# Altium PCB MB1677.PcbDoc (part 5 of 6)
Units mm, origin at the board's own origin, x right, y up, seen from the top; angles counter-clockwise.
Board outline 78 x 105 mm, 6 copper layers (Top Layer, Signal Layer 1, Signal Layer 2, Signal Layer 3, Signal Layer 4, Bottom Layer), stack 1.574 mm thick; 395 components, 320 nets, 1673 pads, 974 vias.

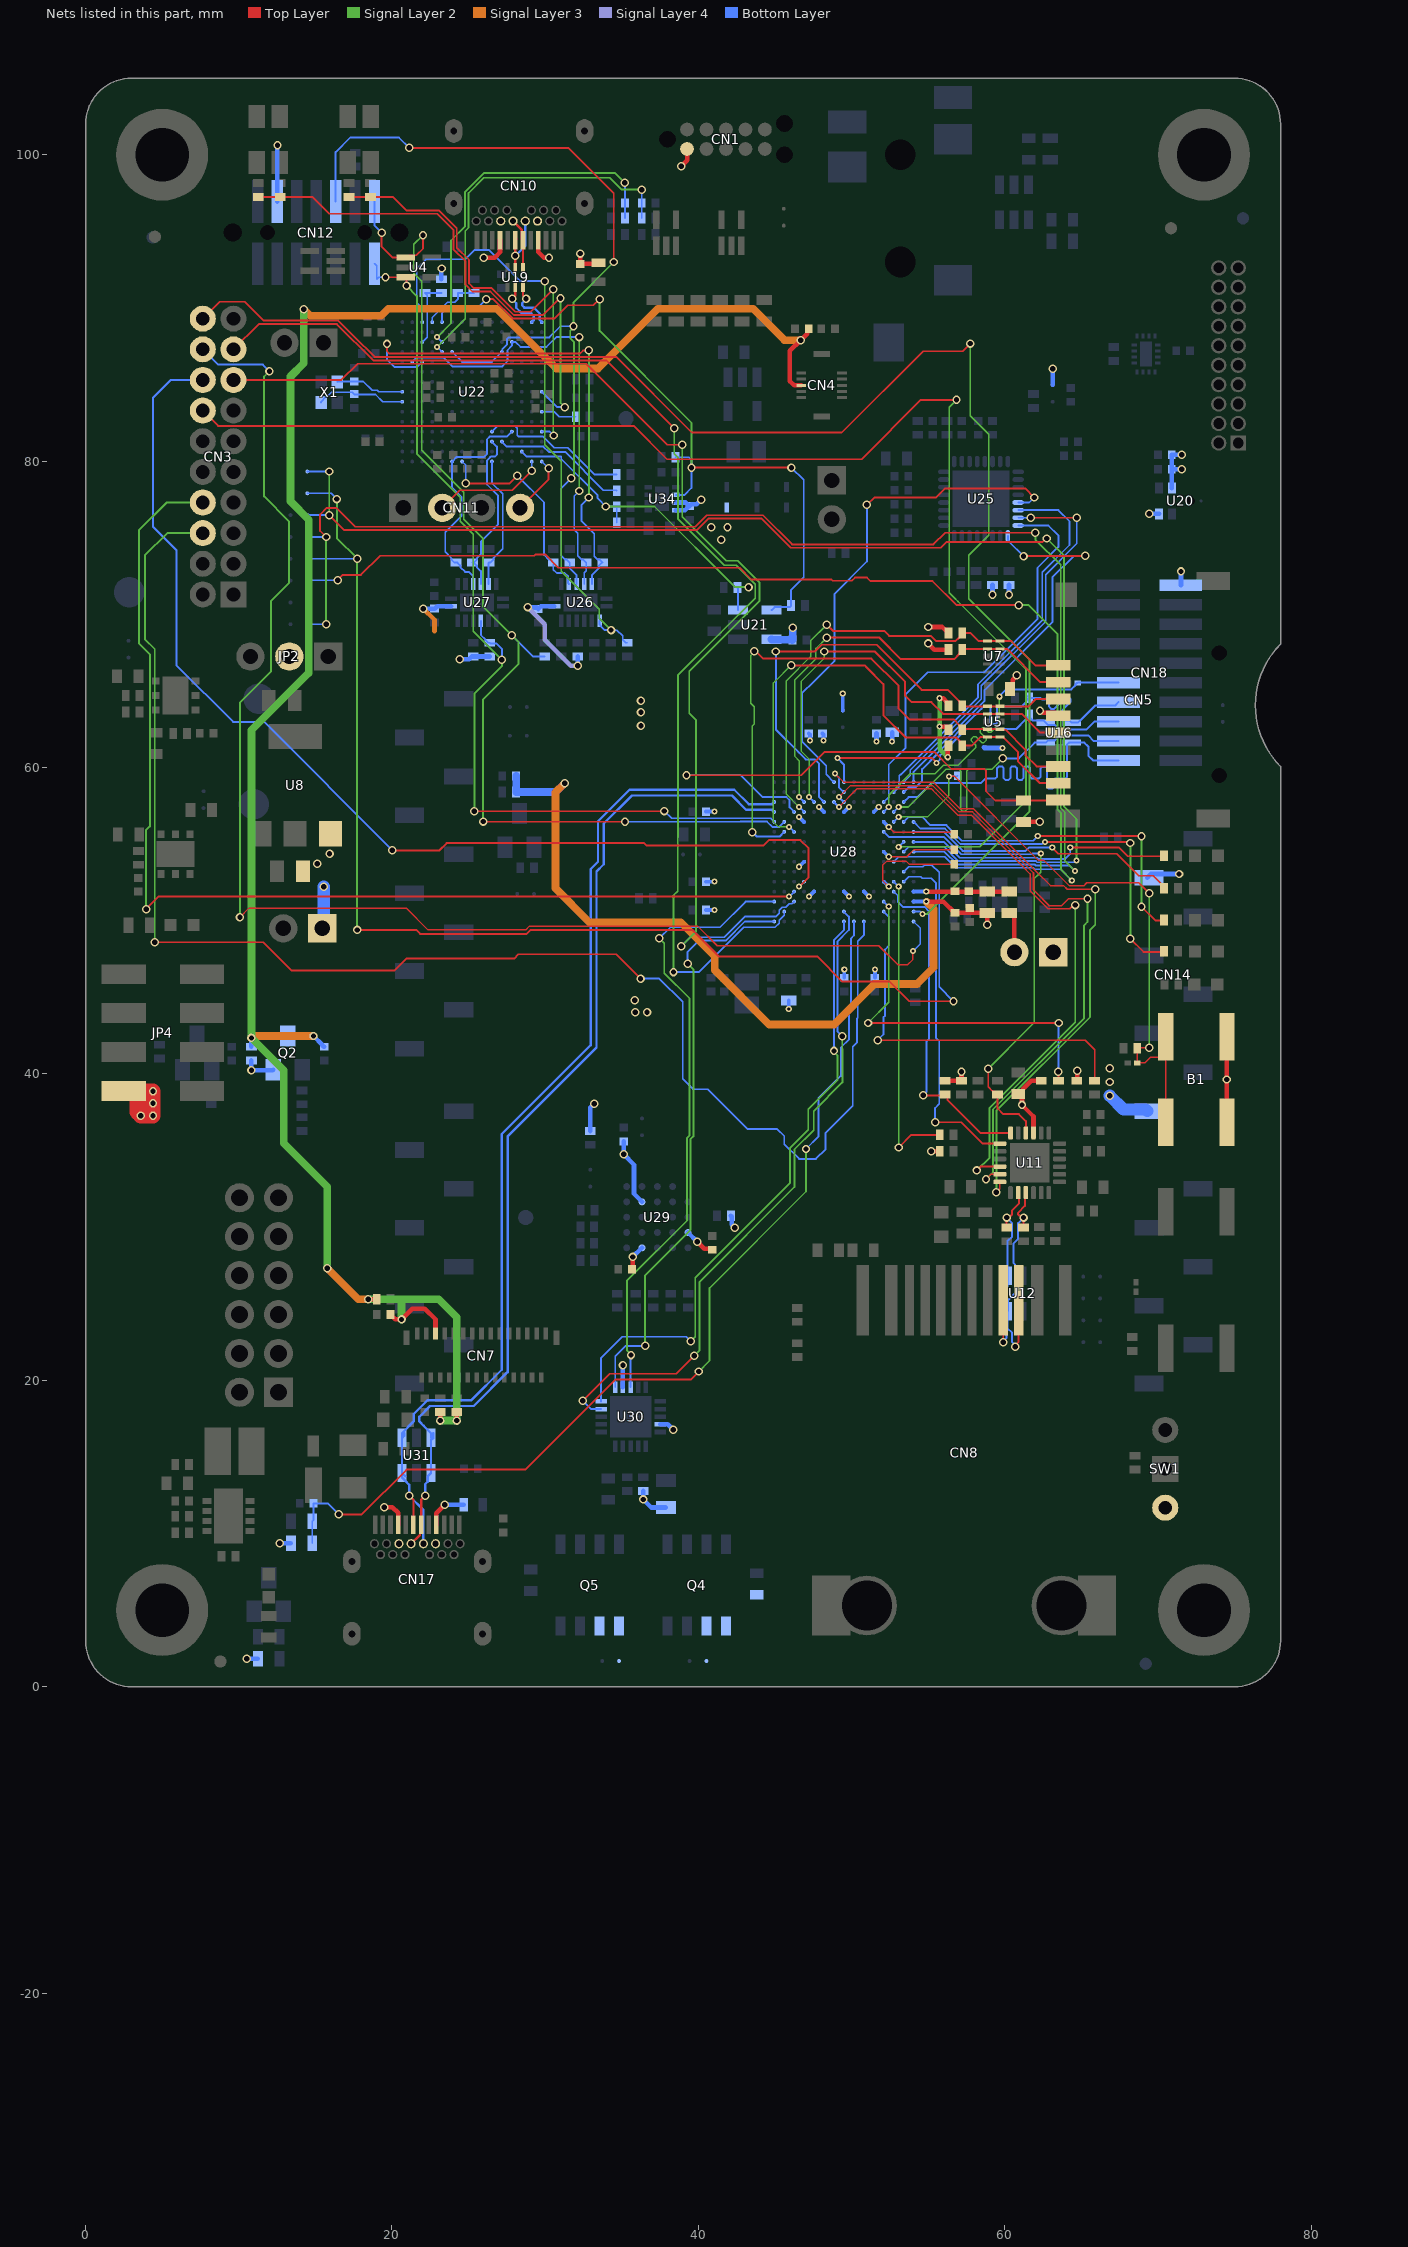
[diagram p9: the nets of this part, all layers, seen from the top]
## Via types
v1: diameter 0.55, hole 0.35, Top Layer to Bottom Layer, tented both sides, 762 vias
v2: diameter 0.4, hole 0.2, Top Layer to Bottom Layer, tented both sides, 203 vias
v3: diameter 0.6, hole 0.3, Top Layer to Bottom Layer, tented both sides, 9 vias

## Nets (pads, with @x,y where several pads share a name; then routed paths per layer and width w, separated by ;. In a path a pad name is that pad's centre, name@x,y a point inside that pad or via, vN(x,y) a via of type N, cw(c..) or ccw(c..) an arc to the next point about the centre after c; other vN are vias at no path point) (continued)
RMII_MDC: U11.13 U28.L2 | length 23
  Top Layer w0.12: v1(55.45,36.85) 57.15,36.85 58.55,35.45 U11.13@59.675,35.45
  Bottom Layer w0.12: U28.L2@53.4,52.55 53.725,52.875 54.5,52.875 54.6,52.775 55.193,52.775 55.5,52.468 55.5,44.275 55.5,42.375 55.725,42.15 55.725,41.625 55.725,38.05 55.45,37.775 v1(55.45,36.85)
RMII_MDIO: R34.1 U11.12 U28.M3 | length 22.1
  Top Layer w0.12: v1(54.675,38.6) 56.05,38.6 R34.1@56.1,38.65 56.265,38.485 56.265,38.285 58.4,36.15 U11.12@60.375,36.15
  Bottom Layer w0.12: U28.M3@52.75,51.9 53.035,51.615 53.035,51.212 53.347,50.9 54.775,50.9 55.05,50.625 55.05,42.275 54.9,42.125 54.9,38.825 v1(54.675,38.6)
RMII_REF_CLK: R37.1 U28.L3 | length 20.5
  Top Layer w0.12: v1(53.075,35.2) 53.9,36.025 R37.1@55.75,36.025
  Signal Layer 2 w0.1: 53.075,41.625 v2(53.075,52.225)
  Signal Layer 2 w0.12: v1(53.075,35.2) 53.075,41.625
  Bottom Layer w0.13: U28.L3@52.75,52.55 v2(53.075,52.225)
RMII_RX_ER: R29.1 U11.10 U28.F4 | length 32.2
  Top Layer w0.12: v1(58.925,40.35) 58.925,39.15 59.23,38.845 59.33,38.845 R29.1@59.525,38.65 59.525,37.75 59.9,37.375 60.925,37.375 61.375,36.925 U11.10@61.375,36.15
  Signal Layer 2 w0.1: 60.2,41.625 61.925,43.35 61.925,52.75 62.125,52.95
  Signal Layer 2 w0.12: v1(58.925,40.35) 60.2,41.625 ; 62.125,52.95 62.35,53.175 v2(62.35,54.4)
  Bottom Layer w0.12: U28.F4@52.1,55.8 52.425,55.475 56.016,55.475 57.156,54.335 61.752,54.335 61.817,54.4 v2(62.35,54.4)
RMII_RXD0: R31.1 U28.N4 | length 24.9
  Top Layer w0.1: v1(51.075,43.325) 62.125,43.325
  Top Layer w0.12: 62.125,43.325 v1(63.525,43.325) ; R31.1@63.5,39.55 63.5,40.125 v1(63.5,40.15)
  Signal Layer 2 w0.1: v1(51.075,43.325) 52.425,44.675 v2(52.425,50.925)
  Bottom Layer w0.12: v1(63.5,40.15) 63.5,43.3 v1(63.525,43.325)
  Bottom Layer w0.13: U28.N4@52.1,51.25 v2(52.425,50.925)
RMII_RXD1: R33.1 U28.P4 | length 25.3
  Top Layer w0.12: v1(51.7,42.2) 62.125,42.2 65.25,42.2 65.55,41.9 65.875,41.575 65.875,39.575 R33.1@65.85,39.55
  Bottom Layer w0.12: v1(51.7,42.2) 52.075,42.575 52.075,43.69 52.185,43.8 52.185,48.124 52.425,48.364 52.425,50.275 U28.P4@52.1,50.6
RMII_TX_EN: U11.16 U28.C9 | length 42
  Top Layer w0.1: v2(49.175,57.425) 50.375,58.625 55.2,58.625 55.512,58.312 56.925,56.9 57.809,56.9 61.3,53.409 61.392,53.317 61.65,53.059 61.65,51.958 62.125,51.483 62.823,50.785 64.238,50.785 64.478,51.025 v1(64.6,51.025)
  Top Layer w0.12: v1(58.175,33.7) 58.425,33.95 U11.16@59.675,33.95
  Signal Layer 2 w0.12: v1(58.175,33.7) 59.01,34.535 59.01,37.782 64.6,43.372 v1(64.6,51.025)
  Bottom Layer w0.13: U28.C9@48.85,57.75 v2(49.175,57.425)
RMII_TXD0: U11.17 U28.C8 | length 43.2
  Top Layer w0.1: v2(49.175,58.075) 49.925,58.825 55.283,58.825 57.008,57.1 57.892,57.1 61.875,53.117 61.875,52.016 62.029,51.862 62.906,50.985 63.71,50.985 64.175,51.45 65.375,51.45 v1(65.4,51.425)
  Top Layer w0.12: v1(58.775,33.125) 59.1,33.45 U11.17@59.675,33.45
  Signal Layer 2 w0.12: v1(58.775,33.125) 59.23,33.58 59.23,37.691 65.175,43.636 65.175,49.7 65.4,49.925 v1(65.4,51.425)
  Bottom Layer w0.13: v2(49.175,58.075) U28.C8@49.5,57.75
RMII_TXD1: U11.18 U28.B8 | length 44.8
  Top Layer w0.1: v2(48.925,59.6) 49.5,59.025 55.366,59.025 56.095,58.295 57.091,57.3 57.975,57.3 62.125,53.15 62.978,52.297 63.828,52.297 64.075,52.05 v1(65.9,52.05)
  Top Layer w0.12: v1(59.45,32.275) 59.675,32.5 U11.18@59.675,32.95
  Signal Layer 2 w0.12: v1(59.45,32.275) 59.45,37.6 65.565,43.715 65.565,49.415 65.9,49.75 v1(65.9,52.05)
  Bottom Layer w0.12: v2(48.925,59.6) 49.175,59.35 49.175,58.725 U28.B8@49.5,58.4
SAI2_FS_A: U25.1 U28.A1 | length 25.6
  Top Layer w0.12: v1(61.225,73.8) v1@65.25,73.8
  Bottom Layer w0.1: 55,60.669 55,60.683
  Bottom Layer w0.12: U28.A1@54.05,59.05 54.05,59.719 55,60.669 ; 55,60.683 58.686,64.369 58.686,65.061 63.11,69.485 63.11,72.413 64.522,73.825 v1(65.25,73.825) ; U25.1@60.2,75.125 60.2,74.851 60.276,74.775 60.276,74.749 v1(61.225,73.8)
SAI2_MCLK_A: U25.30 U28.B3 | length 26.1
  Bottom Layer w0.12: U28.B3@52.75,58.4 53.075,58.725 53.075,59.063 53.115,59.103 53.115,59.47 53.185,59.54 53.22,59.54 58.246,64.566 58.246,65.421 62.45,69.625 62.45,72.75 64.225,74.525 64.225,76.075 63.5,76.8 U25.30@60.875,76.8
SAI2_SCK_A: U25.31 U28.A2 | length 25.8
  Top Layer w0.12: v1(61.7,76.3) v1(64.7,76.3)
  Bottom Layer w0.12: U28.A2@53.4,59.05 53.4,59.077 53.83,59.507 53.83,59.839 58.466,64.475 58.466,64.888 58.466,65.33 62.67,69.534 62.67,72.595 64.7,74.625 v1(64.7,76.3) ; U25.31@60.875,76.3 v1(61.7,76.3)
SAI2_SD_A: U25.32 U28.C4 | length 27.2
  Bottom Layer w0.12: U28.C4@52.1,57.75 52.425,58.075 52.425,60.2 53.525,61.3 53.525,64.775 54.975,66.225 58.66,66.225 62.125,69.69 62.125,73.025 63.5,74.4 63.5,75.15 62.85,75.8 U25.32@60.875,75.8
SAI2_SD_B: U25.29 U28.A9 | length 33.5
  Top Layer w0.12: v1(51,77.15) 51.475,77.625 55.5,77.625 56.1,78.225 61.325,78.225 v1(61.925,77.625)
  Bottom Layer w0.12: U28.A9@48.85,59.05 48.35,59.55 48.35,60.125 46.76,61.715 46.76,64.835 47.55,65.625 48.875,66.95 48.875,71.325 51,73.45 v1(51,77.15) ; U25.29@60.875,77.3 61.6,77.3 v1(61.925,77.625)
SDIO1_CK: CN5.5 U5.2 U5.9 U28.C11 | length 28.8
  Top Layer w0.13: v1(48.225,67.575) 51.525,67.575 53.475,65.625 53.5,65.6 53.5,64.7 53.925,64.275 55.207,64.275 55.982,63.5 U5.2@58.865,63.5 U5.9@59.685,63.5 61.1,63.5 62.125,62.475 62.325,62.275 CN5.5@63.5,62.275
  Signal Layer 2 w0.1: v2(47.225,58.075) 47.225,60.55 46.7,61.075 46.7,65.625 48.225,67.15 v1(48.225,67.575)
  Bottom Layer w0.13: v2(47.225,58.075) U28.C11@47.55,57.75
SDIO1_CMD: CN5.3 R13.1 U5.1 U5.10 U28.C10 | length 32
  Top Layer w0.13: v1(45.05,67.575) 47.603,67.575 48.043,68.015 51.635,68.015 54.575,65.075 56.275,65.075 57.035,64.315 57.035,64.215 R13.1@57.225,64.025 57.25,64 U5.1@58.865,64 U5.10@59.685,64 61.55,64 62.025,64.475 CN5.3@63.5,64.475
  Bottom Layer w0.13: v1(45.05,67.575) 45.05,65.625 45.05,62.485 46.55,60.985 47.005,60.53 47.595,60.53 47.875,60.25 47.875,58.075 U28.C10@48.2,57.75
SDIO1_D0: CN5.7 R12.1 U5.4 U5.7 U28.F14 | length 38.5
  Top Layer w0.13: v1(43.65,67.6) 43.75,67.6 44.235,67.115 51.295,67.115 53.05,65.36 53.05,63.875 53.775,63.15 56.655,63.15 57.035,62.77 57.035,62.665 R12.1@57.225,62.475 57.25,62.5 U5.4@58.865,62.5 U5.7@59.685,62.5 59.718,62.467 60.058,62.467 61.35,61.175 61.35,60.8 62.075,60.075 CN5.7@63.5,60.075
  Signal Layer 2 w0.1: v1(43.525,55.775) 43.525,62.725 43.65,62.85 43.65,63.975 43.425,64.2 43.425,67.316 43.65,67.541 v1(43.65,67.6)
  Bottom Layer w0.13: v1(43.525,55.775) 43.8,55.5 45.3,55.5 U28.F14@45.6,55.8
SDIO1_D1: CN5.8 R11.1 U5.5 U5.6 U28.F13 | length 35.1
  Top Layer w0.13: v1(46.05,66.675) 50.85,66.675 50.961,66.564 52.075,65.45 52.075,63.425 53.54,61.96 56.84,61.96 57.035,61.765 57.035,61.615 R11.1@57.225,61.425 57.85,61.425 58.425,62 U5.5@58.865,62 59.875,62 60.85,61.025 60.85,60.425 62.3,58.975 CN5.8@63.5,58.975
  Signal Layer 2 w0.1: v2(45.925,56.125) 45.225,56.125 44.875,56.475 44.875,65.5 45,65.625 v1(46.05,66.675)
  Bottom Layer w0.13: v2(45.925,56.125) U28.F13@46.25,55.8
SDIO1_D2: CN5.1 R18.1 U7.1 U7.10 U28.D12 | length 30.5
  Top Layer w0.13: v1(48.375,69.325) 48.785,68.915 52.135,68.915 52.45,68.6 55.175,68.6 55.525,68.25 56.775,68.25 57.015,68.49 57.035,68.49 57.225,68.68 R18.1@57.225,68.775 57.775,68.775 58.3,68.25 U7.1@58.865,68.25 U7.10@59.685,68.25 60.425,68.25 62,66.675 CN5.1@63.5,66.675
  Signal Layer 2 w0.1: v2(46.575,57.425) 45.75,58.25 45.75,65.665 47.325,67.24 47.325,68.275 v1(48.375,69.325)
  Bottom Layer w0.13: v2(46.575,57.425) U28.D12@46.9,57.1
SDIO1_D3: CN5.2 R16.1 U7.2 U7.9 U28.C12 | length 28.8
  Top Layer w0.13: v1(48.375,68.475) 51.821,68.475 53.221,67.075 56.7,67.075 57.035,67.41 57.035,67.51 R16.1@57.225,67.7 57.275,67.75 U7.2@58.865,67.75 U7.9@59.685,67.75 60.15,67.75 62.325,65.575 CN5.2@63.5,65.575
  Signal Layer 2 w0.1: v2(46.575,58.075) 46.575,60.45 46.275,60.75 46.275,65.695 47.675,67.095 47.675,67.775 v1(48.375,68.475)
  Bottom Layer w0.13: v2(46.575,58.075) U28.C12@46.9,57.75
STLK_LED: R59.2 R60.1 U22.D15 | length 29.1
  Top Layer w0.12: R60.1@17.199,97.25 R59.2@18.6,97.25 20.05,97.25 20.93,96.37 23.056,96.37 24.23,95.196 24.23,93.931 25.025,93.136 25.025,91.6 25.33,91.295 26.516,91.295 28.056,89.755 29.052,89.755 v1(30.526,91.229)
  Signal Layer 2 w0.12: v1(30.526,91.229) 30.526,81.699 v1(30.55,81.675)
  Bottom Layer w0.12: U22.D15@29.775,81.925 30.3,81.925 v1(30.55,81.675)
STLK_OSC_IN: C71.2 U22.G1 X1.1 | length 5.9
  Bottom Layer w0.12: X1.1@15.375,83.825 15.375,83.875 15.69,84.19 15.74,84.19 16.05,84.5 17.4,84.5 C71.2@17.525,84.375 17.55,84.35 18.925,84.35 19.4,83.875 U22.G1@20.675,83.875
STLK_OSC_OUT: C72.1 U22.H1 X1.3 | length 4.5
  Bottom Layer w0.12: X1.3@16.425,85.175 16.45,85.2 C72.1@17.525,85.2 18.125,85.2 18.7,84.625 19.031,84.625 19.131,84.525 U22.H1@20.675,84.525
STLK_SWCLK: CN11.2 U22.A14 | length 7.4
  Top Layer w0.12: CN11.2@23.28,76.95 24.429,78.099 27.849,78.099 v1(29.125,79.375)
  Bottom Layer w0.1: v1(29.125,79.375) U22.A14@29.125,79.975
STLK_SWDIO: CN11.4 U22.A15 | length 4
  Top Layer w0.12: CN11.4@28.36,76.95 30.225,78.815 v1(30.225,79.525)
  Bottom Layer w0.1: U22.A15@29.775,79.975 v1(30.225,79.525)
STLK_UCPD_CC1_C: C20.1 R46.2 U22.M5 | length 25.2
  Signal Layer 2 w0.12: v2(22.95,87.45) 24.784,89.284 24.784,95.023 24.995,95.234 24.995,97.495 26,98.5 34.225,98.5 35,97.725 v1(36.3,97.725)
  Bottom Layer w0.12: v2(22.95,87.45) U22.M5@23.275,87.125 ; R46.2@36.3,95.875 C20.1@36.3,96.85 v1(36.3,97.725)
STLK_UCPD_CC2_C: C21.1 R47.2 U22.N5 | length 24.2
  Signal Layer 2 w0.12: v2(22.95,88.1) 23.853,89.003 23.853,94.403 24.775,95.325 24.775,97.586 25.989,98.8 34.575,98.8 v1(35.2,98.175)
  Bottom Layer w0.12: v2(22.95,88.1) U22.N5@23.275,87.775 ; R47.2@35.2,95.875 C21.1@35.2,96.85 v1(35.2,98.175)
STLK_USB_CN_N: CN10.A7 CN10.B7 U19.2 | length 4.4
  Top Layer w0.155: U19.2@28.05,92.65 v1(28.05,93.4) CN10.A7@28.05,94.42 CN10.A7@28.122,94.493
  Bottom Layer w0.155: v1(28.05,93.4) 28.7,94.05 CN10.B7@28.7,95.67
STLK_USB_CN_P: CN10.A6 CN10.B6 U19.1 | length 3.3
  Top Layer w0.155: CN10.B6@27.9,95.67 28.477,95.092 28.477,94.493 CN10.A6@28.55,94.42 U19.1@28.55,92.65
STLK_USB_N: U19.5 U22.R14 | length 3.4
  Top Layer w0.155: v1(27.85,90.6) 28.05,90.8 U19.5@28.05,91.35
  Bottom Layer w0.155: v1(27.85,90.6) 27.85,90.571 28.109,90.312 28.109,90.017 28.483,89.644 29.091,89.644 29.26,89.475 29.26,89.213 29.125,89.079 U22.R14@29.125,89.075
STLK_USB_P: U19.6 U22.R15 | length 3.4
  Top Layer w0.155: U19.6@28.55,91.35 28.55,90.8 v1(28.75,90.6)
  Bottom Layer w0.155: v1(28.75,90.6) 28.75,90.571 28.49,90.312 28.49,90.175 28.641,90.025 29.248,90.025 29.641,89.633 29.641,89.213 29.775,89.079 U22.R15@29.775,89.075
STLK_VCP_RX: R84.1 U22.C10 U27.5 | length 11.1
  Bottom Layer w0.12: R84.1@25.25,73.375 R84.1@25.345,73.375 ; U27.5@25.8,71.975 25.8,72.825 25.54,73.085 25.54,73.18 R84.1@25.345,73.375 ; U22.C10@26.525,81.275 26.85,80.95 26.85,80.425 26.725,80.3 26.45,80.3 26.41,80.26 26.407,80.26 26.24,80.093 26.24,80.09 26.2,80.05 26.2,78.475 26.925,77.75 26.925,75.875 25.8,74.75 25.8,73.925 25.54,73.665 25.54,73.57 R84.1@25.345,73.375
STLK_VCP_TX: R134.2 U22.A7 U26.3 | length 13.9
  Top Layer w0.12: v1(24.825,78.55) 27.675,78.55 v1(28.175,79.05)
  Bottom Layer w0.1: U22.A7@24.575,79.975 24.825,79.725 v1(24.825,78.55)
  Bottom Layer w0.12: v1(28.175,79.05) 29.925,77.3 29.925,73.875 30.23,73.57 30.33,73.57 R134.2@30.525,73.375 30.525,72.925 30.75,72.7 31.275,72.7 31.493,72.482 31.493,72.032 U26.3@31.55,71.975
STMOD#1: SB5.1 SB9.1 U28.H1 | length 92.8
  Top Layer w0.12: v1(15.7,75.05) 15.3,75.45 15.3,76.508 15.742,76.95 16.375,76.95 17.605,75.72 39.804,75.72 40.554,76.47 44.216,76.47 46.116,74.57 55.345,74.57 56.1,75.325 v1(62,75.325)
  Signal Layer 2 w0.12: v1(15.7,69.35) v1(15.7,75.05) ; v1(62,75.325) 62,74.875 63.65,73.225 63.65,58.55 63.655,58.545 63.655,57.359 63.915,57.099 63.915,53.91 v2(64.575,53.25)
  Bottom Layer w0.12: SB9.1@14.475,69.35 v1(15.7,69.35) ; SB5.1@14.475,75.05 v1(15.7,75.05) ; U28.H1@54.05,54.5 56.058,54.5 56.883,53.675 61.944,53.675 62.019,53.6 64.225,53.6 v2(64.575,53.25)
STMOD#2: SB7.1 SB8.1 U28.J3 | length 82.3
  Top Layer w0.12: v1(16.45,72.225) 16.8,72.575 17.975,72.575 19.225,73.825 29.285,73.825 29.37,73.91 29.99,73.91 30.863,73.037 42.688,73.037 43.45,72.275 48.685,72.275 48.77,72.19 50.01,72.19 50.225,72.405 50.995,72.405 51.225,72.175 55.275,72.175 56.85,70.6 v1(60.9,70.6)
  Signal Layer 2 w0.12: v1(60.9,70.6) 61.55,70.6 63.43,68.72 63.43,57.273 63.675,57.028 63.675,53.325 v2(64.375,52.625)
  Bottom Layer w0.12: SB8.1@14.475,70.775 SB7.1@14.475,72.2 14.5,72.225 v1(16.45,72.225) ; U28.J3@52.75,53.85 53.075,54.175 56.072,54.175 56.792,53.455 61.853,53.455 61.948,53.36 63.64,53.36 v2(64.375,52.625)
STMOD#3: SB3.1 SB6.1 U28.K2 | length 86.6
  Top Layer w0.12: v1(17.725,49.4) 21.575,49.4 21.83,49.145 28.795,49.145 29.05,49.4 39.6,49.4 41.325,47.675 47.75,47.675 49.4,46.025 52.475,46.025 53.75,44.75 v1(56.65,44.75)
  Signal Layer 2 w0.12: v1(16.4,77.525) 16.4,74.975 17.725,73.65 v1(17.725,73.625) v1(17.725,49.4)
  Bottom Layer w0.12: SB6.1@14.475,73.625 v1(17.725,73.625) ; SB3.1@14.475,77.9 16.025,77.9 v1(16.4,77.525) ; U28.K2@53.4,53.2 53.725,53.525 54.656,53.525 54.761,53.63 55.245,53.63 55.72,53.155 55.72,45.68 v1(56.65,44.75)
STMOD#4: SB2.1 SB4.1 U28.H2 | length 88
  Top Layer w0.12: v1(15.9,76.475) 16.875,75.5 39.895,75.5 40.645,76.25 44.125,76.25 46.025,74.35 55.825,74.35 56.2,74.725 62.465,74.725 62.69,74.95 v1(62.75,74.95)
  Signal Layer 2 w0.12: v1(15.9,76.475) v1(15.9,79.325) ; v1(62.75,74.95) 63.875,73.825 63.875,57.45 64.675,56.65 v2(64.675,53.925)
  Bottom Layer w0.12: SB4.1@14.475,76.475 v1(15.9,76.475) ; SB2.1@14.475,79.325 v1(15.9,79.325) ; U28.H2@53.4,54.5 53.725,54.825 56.044,54.825 56.974,53.895 62.035,53.895 62.11,53.82 64.57,53.82 v2(64.675,53.925)
STMOD#8-MOSIS: CN3.8 U28.N13 | length 78.4
  Top Layer w0.12: CN3.8@9.65,85.3 16.7,85.3 17.755,86.355 32.684,86.355 37.964,81.075 v1(38.95,81.075)
  Signal Layer 2 w0.12: v1(38.875,48.325) 39.85,49.3 39.85,63.1 39.4,63.55 39.4,66.285 41.75,68.635 44,70.885 44,72.075 42.575,73.5 41.825,73.5 38.95,76.375 v1(38.95,81.075)
  Bottom Layer w0.12: v1(38.875,48.325) 39.47,48.92 41.683,48.92 43.038,50.275 45.05,50.275 45.275,50.5 45.275,50.678 45.482,50.885 45.71,50.885 45.93,51.105 46.105,51.105 U28.N13@46.25,51.25
STMOD#9-MISOS: CN3.9 U28.P14 | length 81.7
  Top Layer w0.12: CN3.9@9.65,87.3 11.3,88.95 16.4,88.95 18.775,86.575 34,86.575 v1(38.425,82.15)
  Signal Layer 2 w0.12: v1(38.375,46.65) 38.375,51.65 38.65,51.925 38.65,55.435 38.66,55.445 38.66,66.01 41.475,68.825 43.71,71.06 43.71,71.973 42.483,73.2 41.7,73.2 38.66,76.24 38.66,80.24 38.425,80.475 v1(38.425,82.15)
  Bottom Layer w0.12: v1(38.375,46.65) 40.035,46.65 42.96,49.575 45,49.575 45.275,49.85 45.275,50.028 45.6,50.353 U28.P14@45.6,50.6
STMOD#13-ADC: CN3.13 U28.R6 | length 99.8
  Top Layer w0.12: v1(4.512,48.6) 11.6,48.6 13.45,46.75 20.15,46.75 20.93,47.53 27.975,47.53 28.255,47.81 34.64,47.81 v1(36.225,46.225)
  Signal Layer 2 w0.12: v1(4.512,48.6) 4.512,67.738 3.875,68.375 3.875,73.85 5.325,75.3 CN3.13@7.65,75.3
  Bottom Layer w0.12: v1(36.225,46.225) 37.45,46.225 38.975,44.7 38.975,39.675 39.65,39 40.625,39 43.225,36.4 45.15,36.4 45.6,35.95 45.6,35.425 46.575,34.45 47.675,34.45 48.3,35.075 48.3,36.15 50.075,37.925 50.075,41.775 50.35,42.05 50.35,43.6 50.405,43.655 50.405,48.67 50.8,49.065 U28.R6@50.8,49.95
STMOD#14-PWM: CN3.14 U28.M13 | length 72.8
  Top Layer w0.13: v1(3.95,50.752) 3.95,50.775 4.75,51.575 v2(45.925,51.575)
  Signal Layer 2 w0.13: v1(3.95,50.752) 3.95,55.925 4.19,56.165 4.19,67.385 3.475,68.1 3.475,75.475 5.3,77.3 CN3.14@7.65,77.3
  Bottom Layer w0.13: v2(45.925,51.575) U28.M13@46.25,51.9
STMOD#17: CN3.17 U28.G2 | length 90.6
  Top Layer w0.12: CN3.17@7.65,83.3 8.65,82.3 35.775,82.3 37.95,80.125 50.65,80.125 54.525,84 v1(56.85,84)
  Signal Layer 2 w0.12: v2(53.075,54.825) 58.374,54.825 61.385,57.836 61.385,65.625 61.385,66.4 56.945,70.84 56.69,71.095 56.375,71.41 56.375,75.225 56.375,83.525 v1(56.85,84)
  Bottom Layer w0.13: v2(53.075,54.825) U28.G2@53.4,55.15
STMOD#18: CN3.18 U28.L12 | length 71.9
  Top Layer w0.13: v1(20.025,54.6) 23.1,54.6 23.57,55.07 36.455,55.07 36.625,54.9 44.235,54.9 44.6,55.265 46.653,55.265 47.2,54.718 47.2,52.85 v2(46.575,52.225)
  Bottom Layer w0.13: CN3.18@7.65,85.3 5.575,85.3 4.4,84.125 4.4,75.725 5.925,74.2 5.925,66.675 9.625,62.975 11.65,62.975 v1(20.025,54.6) ; v2(46.575,52.225) U28.L12@46.9,52.55
STMOD#19: CN3.19 U28.R1 | length 91.7
  Top Layer w0.1: v1(10.075,50.225) 10.675,50.825 20.925,50.825 22.35,49.4 28.725,49.4 28.975,49.65 39.95,49.65 41.225,48.375 51.775,48.375 53.025,47.125 53.65,47.125 54.003,47.478 v2(54.003,48.027)
  Signal Layer 2 w0.12: v1(10.075,50.225) 10.075,64.225 12.1,66.25 12.1,70.85 13.275,72.025 13.275,76.075 11.65,77.7 11.65,85.525 v1(12,85.875)
  Bottom Layer w0.1: v2(54.003,48.027) 54.003,48.003 54.475,48.475 54.475,49.525 U28.R1@54.05,49.95
  Bottom Layer w0.12: CN3.19@7.65,87.3 8.65,86.3 11.575,86.3 v1(12,85.875)
STMOD#20: CN3.20 U28.P1 | length 100.1
  Top Layer w0.12: CN3.20@7.65,89.3 8.75,90.4 10.4,90.4 11.63,89.17 16.491,89.17 17.543,88.118 18.861,86.8 34.65,86.8 39.58,81.87 49.359,81.87 54.664,87.175 57.25,87.175 v1(57.75,87.675)
  Signal Layer 2 w0.12: v2(54.625,50.45) 54.945,50.45 61.605,57.11 61.605,65.625 61.605,67.07 57.65,71.025 57.65,73.861 58.95,75.161 58.95,81.77 57.75,82.97 57.75,83.225 v1(57.75,87.675)
  Bottom Layer w0.12: U28.P1@54.05,50.6 54.475,50.6 v2(54.625,50.45)
SW_DIR: R132.2 U22.R3 U26.10 | length 40.6
  Signal Layer 2 w0.12: v1(29.975,91.75) 29.975,81.075 31.05,80 31.05,72.8 33.525,70.325 33.525,69.75 v1(34.3,68.975)
  Bottom Layer w0.12: U22.R3@21.975,89.075 21.975,89.975 21.62,90.33 21.62,92.57 22.225,93.175 24.775,93.175 25.375,93.775 26.35,93.775 28.375,91.75 v1(29.975,91.75) ; U26.10@33.55,69.575 33.55,69.325 33.64,69.235 33.9,68.975 v1(34.3,68.975) 34.31,68.965 34.685,68.965 35.06,68.59 35.06,68.345 35.255,68.15 R132.2@35.35,68.15
T_JRCLK: R83.1 U22.A10 U27.6 | length 8.7
  Bottom Layer w0.12: U27.6@26.3,71.975 26.3,73.35 R83.1@26.325,73.375 26.42,73.375 26.615,73.57 26.615,73.665 27.225,74.275 27.225,77.875 26.525,78.575 U22.A10@26.525,79.975
T_JTDI: R136.1 U22.L3 U26.6 | length 33.9
  Top Layer w0.12: v1(19.675,87.65) 19.675,87.175 19.83,87.02 32.27,87.02 32.473,87.223 32.848,87.223 v1@32.85,87.225
  Signal Layer 2 w0.12: v1(32.85,77.625) v1(32.85,87.25)
  Bottom Layer w0.12: v1(19.675,87.65) 19.675,86.625 20.15,86.15 21.65,86.15 U22.L3@21.975,86.475 ; v1(32.85,77.625) 32.378,77.153 32.378,76.09 33.2,75.267 33.2,73.8 33.43,73.57 33.555,73.57 R136.1@33.75,73.375 33.705,73.375 33.51,73.18 33.51,73.01 33.05,72.55 U26.6@33.05,71.975
T_MCO: R75.1 U22.F15 | length 2.4
  Bottom Layer w0.12: U22.F15@29.775,83.225 30.6,83.225 30.925,82.9 R75.1@32,82.9
T_PWR_EN: R137.2 R139.2 U21.4 U22.R5 U34.2 | length 47.5
  Top Layer w0.12: v1(26.15,90.575) 26.614,90.575 27.874,89.315 30.617,89.315 31.477,90.175 33.15,90.175 v1(33.55,90.575) ; v1(39.55,79.575) v1(46.075,79.575)
  Signal Layer 2 w0.12: v1(33.55,90.575) 33.55,88.5 39.55,82.5 v1(39.55,79.575)
  Bottom Layer w0.12: U22.R5@23.275,89.075 23.275,89.675 23.65,90.05 25.625,90.05 v1(26.15,90.575) ; R137.2@38.5,80.25 39.359,80.25 39.55,80.059 v1(39.55,79.575) 39.55,78.25 39.1,77.8 U34.2@38.525,77.8 ; U21.4@44.775,70.275 44.975,70.475 45.95,70.475 R139.2@46.05,70.575 46.05,71.6 46.875,72.425 46.875,78.775 v1(46.075,79.575)
T_PWR_EXT: R64.1 R65.1 U22.R4 | length 3.9
  Bottom Layer w0.12: U22.R4@22.625,89.075 22.625,89.375 23.625,90.375 24.1,90.375 24.3,90.575 R64.1@24.3,90.975 R65.1@25.35,90.975
T_PWR_INT: R74.2 R87.2 R138.2 U21.3 U22.B13 | length 22.7
  Signal Layer 2 w0.12: v1(33.96,77.04) 37.135,77.04 42.4,71.775 v1(43.275,71.775)
  Bottom Layer w0.12: U22.B13@28.475,80.625 28.8,80.3 31.05,80.3 31.05,80.14 33.422,77.768 33.422,77.578 v1(33.96,77.04) 34.66,77.04 R87.2@34.675,77.025 R74.2@34.675,75.975 ; U21.3@42.575,70.275 42.575,71.725 R138.2@42.55,71.75 42.575,71.775 v1(43.275,71.775)
T_PWR_LED: R130.2 R131.2 U22.H15 | length 34.1
  Top Layer w0.12: R131.2@11.275,97.25 R130.2@12.709,97.25 14.79,97.25 15.89,96.15 22.965,96.15 24.01,95.105 24.01,93.84 24.805,93.045 24.805,91.509 25.239,91.075 26.425,91.075 27.965,89.535 29.855,89.535 30.945,90.625 v1(31,90.625)
  Signal Layer 2 w0.12: v1(31,90.625) 31,83.8 v1(31.275,83.525)
  Bottom Layer w0.12: U22.H15@29.775,84.525 30.775,83.525 v1(31.275,83.525)
T_PWR_SEL1: R86.2 U22.D10 | length 9.9
  Bottom Layer w0.12: U22.D10@26.525,81.925 26.875,82.275 28.05,82.275 28.175,82.15 28.175,81.7 28.275,81.6 29.875,81.6 30.6,80.875 31.475,80.875 33.225,79.125 R86.2@34.675,79.125
T_PWR_SEL2: R128.2 U22.C11 | length 8.8
  Bottom Layer w0.12: U22.C11@27.175,81.275 27.5,80.95 29.883,80.95 30.233,80.6 31.3,80.6 33.8,78.1 34.65,78.1 R128.2@34.675,78.075
T_SWCLK: CN12.9 R135.1 U22.M6 U22.M11 U26.4 | length 60.2
  Top Layer w0.12: v1(21.125,100.45) 31.5,100.45 34.475,97.475 v1(34.475,93)
  Signal Layer 2 w0.12: v1(31.7,78.875) 31.875,79.05 31.875,87.784 31.64,88.019 31.64,88.515 v1@31.85,88.725 ; v1(31.85,88.8) 31.85,90.375 v1(34.475,93)
  Bottom Layer w0.12: CN12.9@16.32,96.95 16.32,100.17 17.275,101.125 20.45,101.125 v1(21.125,100.45) ; U22.M6@23.925,87.125 24.575,86.475 26.525,86.475 U22.M11@27.175,87.125 27.196,87.146 27.196,87.296 27.5,87.6 27.5,87.95 27.625,88.075 30.275,88.075 31,88.8 v1(31.85,88.8) ; v1(31.7,78.875) 31.05,78.225 31.05,73.825 31.305,73.57 31.405,73.57 R135.1@31.6,73.375 31.6,73 32.05,72.55 U26.4@32.05,71.975
T_SWDIO: R1.1 U22.L2 U22.N12 U26.5 | length 29.6
  Signal Layer 2 w0.12: v1(32.225,78.05) v1(32.225,88.1)
  Bottom Layer w0.12: U22.L2@21.325,86.475 21.625,86.775 23.35,86.775 23.939,86.186 27.205,86.186 27.54,86.521 27.54,87.243 27.825,87.528 U22.N12@27.825,87.775 28.072,87.775 28.397,87.45 30.075,87.45 30.725,88.1 v1(32.225,88.1) ; v1(32.225,78.05) 31.9,77.725 31.9,75.525 32.125,75.3 32.125,73.825 32.38,73.57 32.48,73.57 R1.1@32.675,73.375 32.675,72.85 32.55,72.725 U26.5@32.55,71.975
T_SWO: R82.1 U22.A6 U22.D12 U27.4 | length 15
  Bottom Layer w0.12: U27.4@25.3,71.975 25.29,71.985 25.29,72.485 25,72.775 24.775,72.775 24.465,73.085 24.465,73.18 24.27,73.375 R82.1@24.175,73.375 24.08,73.375 23.885,73.57 23.885,73.665 23.475,74.075 23.475,75.35 24.55,76.425 24.55,77.65 23.925,78.275 U22.A6@23.925,79.975 24.225,80.275 26.025,80.275 26.2,80.45 26.2,81.425 26.375,81.6 27.5,81.6 U22.D12@27.825,81.925
T_VCC_AIN: R66.1 R67.1 U22.N3 | length 4.5
  Bottom Layer w0.12: U22.N3@21.975,87.775 22.3,88.1 22.3,90.825 R67.1@22.15,90.975 R66.1@23.225,90.975
TD_N: CN8.4 R113.1 U11.20 U12.4 | length 14.3
  Top Layer w0.13: v1(59.9,22.475) CN8.4@59.9,25.22 ; R113.1@60.125,29.975 v1(60.125,30.625) 60.239,30.625 60.368,30.754 60.409,30.754 60.485,30.83 60.485,31.096 60.935,31.546 60.935,32.19 U11.20@60.875,32.25
  Bottom Layer w0.13: v1(59.9,22.475) 59.9,22.563 60.098,22.761 60.098,22.942 59.997,23.042 59.9,23.14 59.71,23.33 59.71,25.275 60.175,25.74 U12.4@60.175,26.82 60.175,29.075 60.485,29.385 60.485,30.265 v1(60.125,30.625)
TD_P: CN8.3 R112.1 U11.21 U12.3 | length 15
  Top Layer w0.13: v1(60.675,22.2) 60.675,22.272 60.89,22.486 60.89,25.19 CN8.3@60.92,25.22 ; R112.1@61.225,29.975 v1(61.225,30.625) 61.111,30.625 60.982,30.754 60.941,30.754 60.865,30.83 60.865,30.938 61.315,31.388 61.315,32.19 U11.21@61.375,32.25
  Bottom Layer w0.13: v1(60.675,22.2) 60.675,22.289 60.478,22.486 60.478,23.099 60.175,23.402 U12.3@60.175,24.52 60.211,24.556 60.211,25.239 60.66,25.688 60.66,27.57 60.555,27.675 60.555,28.918 60.865,29.228 60.865,30.265 v1(61.225,30.625)
TRACECLK: CN18.12 U17.1 U28.D4 | length 22.6
  Signal Layer 2 w0.1: v2(52.425,57.425) 52.425,58.193 53.832,59.6 55.45,59.6 56,60.15 56.95,60.15 58.075,61.275 58.11,61.31 58.11,61.452 57.821,61.741 57.821,61.883 57.962,62.024 58.104,62.024 58.496,61.632 58.637,61.632 58.779,61.773 58.779,61.915 58.387,62.307 58.387,62.448 58.528,62.59 58.669,62.59 58.959,62.3 59.1,62.3 59.3,62.5 59.65,62.85 v2(59.65,64.625)
  Bottom Layer w0.13: U28.D4@52.1,57.1 v2(52.425,57.425) ; v2@59.65,64.65 60.11,65.11 64.348,65.11 64.615,65.377 64.615,65.425 64.715,65.525 U17.1@64.762,65.525 64.778,65.54 CN18.12@67.415,65.54
TRACED0: CN18.14 R97.1 U16.4 U28.B2 | length 24
  Bottom Layer w0.1: R97.1@61.37,64.803 61.37,64.755 R97.1@61.575,64.55
  Bottom Layer w0.13: U28.B2@53.4,58.4 53.725,58.725 54.2,58.725 54.6,59.125 54.6,59.9 55.55,60.85 55.55,60.909 58.081,63.44 58.475,63.834 58.641,64 58.97,64 59.078,63.893 59.078,62.944 59.185,62.837 59.4,62.837 59.508,62.944 59.508,63.893 59.615,64 60.075,64 61.125,64 61.385,64.26 61.385,64.36 R97.1@61.575,64.55 62.325,64.55 62.4,64.475 62.446,64.429 62.598,64.429 62.823,64.654 62.975,64.654 63.127,64.502 63.127,64.35 62.897,64.12 62.897,63.968 63.049,63.816 63.201,63.816 63.999,64.614 64.151,64.614 64.303,64.462 64.303,64.31 63.51,63.517 63.51,63.365 63.604,63.271 63.65,63.225 63.815,63.06 64.24,63.06 U16.4@64.375,62.925 64.775,62.925 64.91,63.06 65.901,64.051 67.196,64.051 CN18.14@67.415,64.27
TRACED1: CN18.16 R98.1 U16.3 U28.A8 | length 22.2
  Top Layer w0.13: v2(49.075,60.625) 55.225,60.625 v2(55.55,60.3)
  Bottom Layer w0.13: v2(49.075,60.625) 49.5,60.2 U28.A8@49.5,59.05 ; v2(55.55,60.3) 55.78,60.53 55.78,60.813 57.467,62.5 60.73,62.5 61.37,63.14 61.385,63.14 61.575,63.33 61.765,63.14 61.765,63.136 61.841,63.06 62.54,63.06 62.81,62.79 63.26,62.79 63.57,62.48 65.33,62.48 65.85,63 CN18.16@67.415,63
TRACED2: CN18.18 U16.1 U28.D3 | length 22.1
  Signal Layer 2 w0.1: v2(53.075,57.425) 53.7,57.425 56.15,59.875 56.575,59.875 57.025,59.875 57.125,59.775 57.125,57.261 57.225,57.161 57.425,57.161 57.525,57.261 57.525,59.775 57.625,59.875 58.258,59.875 59.15,59.875 v1(59.875,60.6)
  Bottom Layer w0.13: U28.D3@52.75,57.1 v2(53.075,57.425) ; v1(59.875,60.6) 60.925,60.6 61.95,61.625 U16.1@62.675,61.625 62.81,61.76 63.26,61.76 63.6,62.1 65.45,62.1 65.82,61.73 CN18.18@67.415,61.73
TRACED3: CN18.20 U16.5 U28.C2 | length 24.4
  Bottom Layer w0.13: U28.C2@53.4,57.75 53.725,58.075 54.3,58.075 55.2,58.975 58.425,58.975 58.75,59.3 59.325,59.3 59.39,59.3 59.498,59.407 59.498,59.959 59.605,60.066 59.82,60.066 59.928,59.959 59.928,59.31 60.035,59.203 60.25,59.203 60.358,59.31 60.358,59.959 60.465,60.066 60.68,60.066 60.788,59.959 60.788,59.31 60.895,59.203 61.11,59.203 61.218,59.31 61.218,59.959 61.325,60.066 61.54,60.066 61.648,59.959 61.648,59.407 61.755,59.3 62.077,59.3 62.168,59.3 62.233,59.3 62.34,59.407 62.34,59.942 62.448,60.05 62.663,60.05 62.77,59.942 62.77,58.727 62.878,58.62 63.093,58.62 63.2,58.727 63.2,59.193 63.308,59.3 63.7,59.3 63.98,59.3 64.056,59.376 64.056,61.49 64.191,61.625 U16.5@64.375,61.625 65.2,61.625 65.45,61.375 65.45,60.775 65.765,60.46 CN18.20@67.415,60.46
UCPD_CC1: U28.R15 U30.1 | length 37.9
  Signal Layer 2 w0.12: v1(36.525,22.25) 36.525,26.85 38.675,29 39.48,29.805 39.48,35.73 39.675,35.925 39.675,41.625 39.675,46.825 v1(39.3,47.2)
  Bottom Layer w0.12: U30.1@34.575,19.55 34.575,21.575 35.25,22.25 v1(36.525,22.25) ; v1(39.3,47.2) 39.3,47.975 40.025,48.7 41.774,48.7 43.024,49.95 U28.R15@44.95,49.95
UCPD_CC2: U28.N15 U30.3 | length 40.4
  Signal Layer 2 w0.12: v1(35.6,21.65) 35.6,21.685 35.35,21.935 35.35,26.525 39.26,30.435 39.26,35.821 39.425,35.986 39.425,41.625 39.425,44.925 37.775,46.575 37.775,48.525 v1(37.45,48.85)
  Bottom Layer w0.12: U30.3@35.575,19.55 35.575,21.625 v1(35.6,21.65) ; v1(37.45,48.85) 38.18,49.58 41.409,49.58 43.079,51.25 43.175,51.25 U28.N15@44.95,51.25
UCPD_FLT: U28.P8 U30.19 | length 43.5
  Top Layer w0.12: v1(32.45,18.675) 34.2,20.425 38.55,20.425 v1(39.725,21.6)
  Signal Layer 2 w0.1: 49.4,41.625 v1(49.4,42.45)
  Signal Layer 2 w0.12: v1(39.725,21.6) 40.075,21.95 40.075,26.425 46.275,32.625 46.275,35.075 47.525,36.325 47.525,37.575 49.4,39.45 49.4,41.625
  Bottom Layer w0.12: v1(32.45,18.675) 33,18.125 U30.19@33.65,18.125 ; v1(49.4,42.45) 49.07,42.78 49.07,48.64 49.825,49.395 49.825,50.275 U28.P8@49.5,50.6
UCPD_PWR: U28.R8 U30.20 | length 41.1
  Signal Layer 2 w0.12: v1(39.5,22.55) 39.8,22.85 39.8,26.7 45.975,32.875 45.975,35.15 47.175,36.35 47.175,37.7 49.075,39.6 49.075,41.215 48.85,41.44 v1(48.85,41.5)
  Bottom Layer w0.12: U30.20@33.65,18.625 33.65,21.475 35.025,22.85 39.2,22.85 v1(39.5,22.55) ; v1(48.85,41.5) 48.85,48.731 49.5,49.381 U28.R8@49.5,49.95
UCPD_SNK03: Q5.5 Q5.6 SB29.2
UCPD_SOURCE: C125.2 Q4.5 Q4.6 SB28.2
USB_FS_N: CN17.A7 CN17.B7 U28.D15 U31.1 U31.6 | length 67.2
  Top Layer w0.155: CN17.B7@21.25,9.335 21.828,9.912 21.828,10.513 CN17.A7@21.9,10.585 21.9,12.2 v1(22.175,12.475)
  Bottom Layer w0.155: v1(22.175,12.475) 22.175,13.225 22.328,13.378 22.328,13.728 U31.1@22.55,13.95 22.55,16.095 22.7,16.245 U31.6@22.7,16.545 ; U31.6@22.55,16.25 22.55,16.55 22.073,17.028 21.79,17.31 21.79,17.627 22.489,18.325 25.339,18.325 27.55,20.536 27.55,35.925 33.35,41.725 33.35,53.215 33.825,53.69 33.825,56.337 35.663,58.175 42.186,58.175 43.127,57.235 44.812,57.235 44.946,57.1 U28.D15@44.95,57.1
USB_FS_P: CN17.A6 CN17.B6 U28.C15 U31.3 U31.4 | length 70.2
  Top Layer w0.155: v1(21.125,12.475) 21.4,12.2 CN17.A6@21.4,10.585
  Bottom Layer w0.155: U31.4@20.65,16.25 20.65,16.55 21.409,17.31 21.409,17.785 22.331,18.706 25.181,18.706 27.169,20.694 27.169,36.083 32.969,41.883 32.969,53.372 33.444,53.847 33.444,56.495 35.505,58.556 42.344,58.556 43.285,57.616 44.812,57.616 44.946,57.75 U28.C15@44.95,57.75 ; U31.4@20.8,16.545 20.8,16.395 20.65,16.245 U31.3@20.65,13.95 ; U31.3@20.872,13.728 U31.3@20.65,13.95 ; CN17.B6@22.05,9.335 22.05,11.541 21.125,12.466 21.125,13.175 20.873,13.427 20.65,13.65 U31.3@20.65,13.95
USD_DETECT: CN5.9 R10.1 U28.D13 | length 35.3
  Top Layer w0.12: v1(39.225,59.5) 46.725,59.5 48.249,61.024 55.401,61.024 56.52,59.905 58.175,59.905 58.67,59.905 58.775,59.8 58.775,58.45 59.375,57.85 R10.1@61.225,57.85 63.475,57.85 CN5.9@63.5,57.875
  Bottom Layer w0.12: v1(39.225,59.5) 42.775,59.5 44.2,58.075 45.75,58.075 45.95,57.875 45.95,57.4 U28.D13@46.25,57.1
USER_LED1: R26.1 U28.E1 | length 23.6
  Top Layer w0.12: v2(62.625,55.15) 68.125,55.15 v1(68.2,55.075) ; v1(68.2,48.825) 69.065,47.96 R26.1@70.4,47.96
  Signal Layer 2 w0.12: v1(68.2,48.825) v1(68.2,55.075)
  Bottom Layer w0.12: U28.E1@54.05,56.45 54.48,56.02 56.094,56.02 57.109,55.005 62.415,55.005 62.56,55.15 v2(62.625,55.15)
USER_LED2: R25.1 U28.E2 | length 22.9
  Top Layer w0.12: v2(62.15,55.525) v1(68.925,55.525) ; v1(68.925,50.925) 69.84,50.01 R25.1@70.4,50.01
  Signal Layer 2 w0.12: v1(68.925,50.925) v1(68.925,55.525)
  Bottom Layer w0.12: U28.E2@53.4,56.45 53.725,56.775 54.6,56.775 55.135,56.24 56.185,56.24 57.2,55.225 61.85,55.225 v2(62.15,55.525)
USER_LED3: R24.1 U28.F1 | length 18.1
  Top Layer w0.12: v2(63.1,54.775) 63.5,54.375 67.3,54.375 68.74,52.935 69.685,52.935 70.205,52.415 70.205,52.32 R24.1@70.4,52.125
  Bottom Layer w0.12: U28.F1@54.05,55.8 56.002,55.8 57.247,54.555 61.355,54.555 61.575,54.775 v2(63.1,54.775)
USER_LED4: R22.1 U28.G1 | length 17.6
  Top Layer w0.12: v2(64.275,54.775) 67.475,54.775 68.04,54.21 R22.1@70.4,54.21
  Bottom Layer w0.12: U28.G1@54.05,55.15 56.03,55.15 57.065,54.115 62.126,54.115 62.201,54.04 63.94,54.04 64.275,54.375 v2(64.275,54.775)
VBUS_SENSE: C122.2 R124.2 R125.1 U28.R7 | length 65.5
  Top Layer w0.12: v1(16.525,11.25) 18.025,11.25 20.95,14.175 28.7,14.175 34.575,20.05 39.5,20.05 v1(40.025,20.575)
  Signal Layer 2 w0.12: v1(40.025,20.575) 40.725,21.275 40.725,26.025 47.025,32.325 v1(47.025,35.1)
  Bottom Layer w0.12: R125.1@14.8,9.37 R124.2@14.8,10.795 14.875,10.87 C122.2@14.875,11.97 15.805,11.97 v1(16.525,11.25) ; v1(47.025,35.1) 47.838,35.913 47.838,38.413 49.3,39.875 49.3,41.625 49.3,41.725 49.835,42.26 49.835,44.27 49.965,44.4 49.965,48.852 50.15,49.038 U28.R7@50.15,49.95
VBUS_STLK: C57.1 C61.2 C65.2 CN10.A4 CN10.A9 CN10.B4 CN10.B9 D2.1 JP4.7 U13.1 U21.5 U34.3 U34.4 | length 20.4
  Top Layer w0.3: v1(26,93.275) 26.7,93.275 27.05,93.625 CN10.A9@27.05,94.42 ; CN10.A4@29.55,94.42 29.55,93.65 29.925,93.275 v1(30.25,93.275) ; v1(32.3,93.55) C57.1@32.3,92.875 33.4,92.875 U13.1@33.475,92.95
  Top Layer w1: JP4.7@3.216,38.875 JP4.7@3.6,38.875 ; JP4.7@3.216,38.875 2.51,38.875 JP4.7@2.5,38.885 3.206,38.885 JP4.7@3.216,38.875 ; JP4.7@3.216,38.875 3.356,38.735 3.356,37.519 v1(3.6,37.275) ; v1(3.6,37.275) 3.6,38.075 4,38.475 ; v1(3.6,37.275) v1(4.4,37.275) v1(4.4,38.075) ; JP4.7@3.6,38.875 4,38.475 ; JP4.7@3.6,38.875 v1(4.4,38.875) ; 4,38.475 v1(4.4,38.875) ; 4,38.475 v1(4.4,38.075) ; v1(4.4,38.075) v1(4.4,38.875)
  Bottom Layer w0.3: U34.4@38.525,76.8 39.125,76.8 C65.2@39.4,77.075 ; U34.3@38.525,77.3 39.175,77.3 C65.2@39.4,77.075 ; v1(40.175,77.475) 39.88,77.18 39.53,77.18 C65.2@39.425,77.075 C65.2@39.4,77.075
  Bottom Layer w0.5: U21.5@44.775,68.375 44.799,68.351 46.099,68.351 46.125,68.325 46.15,68.35 v1(46.15,69.125)
  other v1: 35.875,44.025 36.65,44.025 35.85,44.8 36.25,62.725 36.25,63.6 36.25,64.35 41.5,74.875 40.85,75.675 41.9,75.675
VBUSC: CN17.A4 CN17.A9 CN17.B4 CN17.B9 R121.1 R122.1 R125.2 R127.1 U30.9 U32.1 | length 9.3
  Top Layer w0.3: v1(19.5,11.725) 20.025,11.725 20.4,11.35 CN17.A4@20.4,10.585 ; CN17.A9@22.9,10.585 22.9,11.325 v1(23.45,11.875)
  Bottom Layer w0.3: v1@10.525,1.825 v1(10.53,1.82) R127.1@11.25,1.82 ; v1@12.675,9.375 v1(12.68,9.37) R125.2@13.4,9.37 ; v1(23.45,11.875) U32.1@24.675,11.875 ; R122.1@36.4,12.775 v1(36.4,12.225) 36.925,11.7 R121.1@37.875,11.7 ; U30.9@37.5,17.125 38,17.125 v1(38.35,16.775)
VCP_T_RX: CN12.13 R61.2 U4.1 U28.E14 | length 72.1
  Top Layer w0.12: v1@19.325,94.75 19.325,94 20.025,93.3 21.025,93.3 21.165,93.44 21.59,93.44 22.025,93.875 v1(22.025,94.75) ; v1(25.95,56.475) 25.991,56.475 26.066,56.55 26.151,56.465 v1(35.21,56.465)
  Signal Layer 2 w0.12: v1(22.025,94.75) 21.425,94.15 21.425,92.265 21.94,91.75 21.94,82.751 21.94,80.71 24.679,77.971 24.679,76.197 25.95,74.926 25.95,70.5 v1(27.825,68.625) 28.25,68.2 28.25,66.75 25.95,64.45 v1(25.95,56.475)
  Bottom Layer w0.12: CN12.13@18.86,96.95 18.86,95.365 v1(19.325,94.9) ; v1(27.825,68.625) 29.2,67.25 R61.2@29.975,67.25 ; v1(35.21,56.465) 42.731,56.465 42.736,56.47 44.48,56.47 44.825,56.125 45.275,56.125 U28.E14@45.6,56.45
VCP_T_TX: CN12.14 R3.1 U4.3 U27.12 U28.E15 | length 64.2
  Top Layer w0.1: 36.4,57.15 37.765,57.15 v1(37.775,57.16)
  Top Layer w0.12: v1(19.575,92) 19.591,92 19.691,91.9 19.791,92 20.408,92 U4.3@20.517,91.892 ; U4.3@20.9,92 20.95,91.926 v1(20.95,91.45) ; v1(25.375,57.15) 36.4,57.15
  Signal Layer 2 w0.12: v1(20.95,91.45) 21.625,90.775 21.625,80.475 24.459,77.641 24.459,76.066 25.3,75.225 25.3,68.9 v1(27.175,67.025) 27.175,66.625 25.375,64.825 v1(25.375,57.15)
  Bottom Layer w0.12: CN12.14@18.86,92.886 19,92.746 19,91.925 19.025,91.9 19.125,92 v1(19.575,92) ; U27.12@25.8,69.575 25.8,68.65 26.085,68.365 26.085,68.345 26.28,68.15 R3.1@26.375,68.15 26.433,68.092 26.835,68.092 27.175,67.751 v1(27.175,67.025) ; v1@37.775,57.175 v1(37.775,57.16) 38.25,56.685 42.64,56.685 42.645,56.69 44.71,56.69 U28.E15@44.95,56.45
VDD: B1.1 B1.2 C23.1 C37.2 C44.2 C47.2 C62.1 C63.2 C91.1 C93.1 C119.2 CN1.1 CN5.4 CN12.3 CN14.7 CN18.1 JP2.2 JP6.1 Q2.2 R2.2 R3.2 R10.2 R11.2 R12.2 R13.2 R16.2 R18.2 R30.2 R32.2 R34.2 R35.2 R39.2 R63.2 R66.2 R79.2 R80.2 R100.1 R104.2 R108.1 SB1.1 SW1.2 U11.9 U20.2 U20.5 U26.16 U27.16 U29.B4 U29.D1 U29.E4 U30.2 | length 69.6
  Top Layer w0.3: C47.2@35.675,27.25 35.725,27.3 v1(35.725,28.055) ; v1(38.875,99.25) 39.26,99.635 CN1.1@39.26,100.38 ; v1(39.915,29.055) 40.387,28.583 40.842,28.583 C44.2@40.9,28.525 ; v1(55,68.1) 55.4,67.7 R16.2@56.325,67.7 ; v1(55,69.175) 55.925,69.175 56.125,68.975 56.22,68.975 56.325,68.87 R18.2@56.325,68.775 ; v1(55.2,34.95) R39.2@55.75,34.95 ; v2(55.75,62.675) 55.754,62.671 56.22,62.671 56.325,62.566 R12.2@56.325,62.475 ; v2(55.75,64.525) 55.975,64.525 56.22,64.28 56.22,64.13 R13.2@56.325,64.025 ; R34.2@56.1,39.55 R35.2@57.175,39.55 v1(57.175,40.15) ; v2(56.275,60.675) 56.267,60.683 56.267,61.367 R11.2@56.325,61.425 ; C23.1@60.35,65.125 60.52,65.295 60.52,65.724 60.775,65.979 v1(60.775,66.025) ; R10.2@61.225,56.45 v1(62.275,56.45) ; U11.9@61.875,36.15 61.875,37.225 v1(61.125,37.975) 61.125,38.45 C37.2@60.875,38.7 61,38.7 61.17,38.87 61.17,38.995 61.725,39.55 R30.2@62.375,39.55 ; v1(62.3,63.7) 62.368,63.7 62.493,63.575 63.3,63.575 CN5.4@63.5,63.375 ; R32.2@64.7,39.55 64.725,39.575 v1(64.725,40.2) ; B1.2@74.5,36.837 v1(74.5,39.637) B1.1@74.5,42.437
  Signal Layer 2 w0.3: v2(55.75,64.525) 55.752,64.523 55.752,62.677 v2(55.75,62.675) 55.752,62.673 55.752,61.198 v2(56.275,60.675)
  Signal Layer 3 w0.3: v1(22.05,70.375) 22.775,69.65 22.775,68.9
  Signal Layer 4 w0.3: v1(28.85,70.475) 29.975,69.35 29.975,68.35 31.675,66.65 v1(32.125,66.65)
  Bottom Layer w0.3: R100.1@10.825,40.875 v1(10.825,40.25) 12.225,40.25 Q2.2@12.25,40.275 ; CN12.3@12.51,96.95 12.51,100.61 v1(12.525,100.625) ; v1(22.05,70.375) C93.1@22.775,70.375 22.8,70.375 22.95,70.525 U27.16@23.85,70.525 ; R66.2@23.225,91.875 23.225,92.55 v1(23.25,92.575) ; v1(24.425,67.075) 25.03,67.075 25.205,67.25 R2.2@25.3,67.25 R3.2@26.375,67.25 ; v1(28.85,70.475) 28.881,70.444 29.456,70.444 C91.1@29.55,70.35 29.725,70.525 U26.16@30.6,70.525 ; v1(32.125,66.65) R63.2@32.125,67.25 ; R104.2@32.945,36.275 32.945,37.812 33.183,38.05 v1(33.2,38.05) ; U30.2@35.075,19.55 v1(35.075,20.975) ; C119.2@35.125,35.6 v1(35.125,34.75) 35.8,34.075 35.8,32.17 U29.B4@36.32,31.65 ; v1(35.725,28.055) U29.E4@36.32,28.65 ; U29.D1@39.32,29.65 v1(39.915,29.055) ; R108.1@42.12,30.75 42.168,30.702 42.168,30.157 v1(42.375,29.95) ; v1(59.2,71.275) R80.2@59.2,71.925 ; v1(60.275,71.275) R79.2@60.275,71.925 ; SB1.1@63.125,84.975 v1(63.125,86.025) ; CN14.7@69.298,52.815 69.534,53.05 v1(71.375,53.05) ; v1(69.431,76.562) U20.5@70.081,76.562 ; U20.2@70.903,78.238 C62.1@70.903,79.463 ; CN18.1@71.485,71.89 71.5,71.905 v1(71.5,72.8) ; v1(71.553,79.463) C62.1@70.903,79.463 ; v1(71.553,80.413) C63.2@70.903,80.413 C62.1@70.903,79.463
VDD_LCD: C3.2 C48.1 C117.2 CN4.8 CN7.25 Q2.3 R41.1 R43.2 R44.2 R100.2 | length 143.3
  Top Layer w0.3: v1(18.45,25.3) R41.1@19,25.3 ; C48.1@19.9,24.3 19.9,24.275 20.2,23.975 v1(20.625,23.975) 21.325,24.675 22.15,24.675 22.84,23.985 CN7.25@22.84,23.05 ; v1(23.15,17.375) R43.2@23.15,17.925 ; v1(24.225,17.375) R44.2@24.225,17.925 ; CN4.8@46.725,84.95 46.25,84.95 46.076,85.124 45.975,85.225 45.975,87.2 v1(46.675,87.9) 47.095,88.32 47.095,88.545 C3.2@47.2,88.65
  Signal Layer 2 w0.5: v1(14.25,89.925) 14.25,86.4 13.375,85.525 13.375,77.375 14.575,76.175 14.575,66.175 10.825,62.425 v1(10.825,42.35) 12.925,40.25 12.925,35.475 15.775,32.625 v1(15.775,27.325) ; v1(18.45,25.3) 20.625,25.3 ; v1(20.625,23.975) 20.625,25.3 ; v1(23.15,17.375) v1(24.225,17.375) 24.225,24.125 23.05,25.3 20.625,25.3
  Signal Layer 3 w0.5: v1(10.825,42.35) 10.95,42.475 v1(14.875,42.475) ; v1(14.25,89.925) 14.675,89.5 19.3,89.5 19.75,89.95 26.825,89.95 30.725,86.05 33.45,86.05 37.35,89.95 ; v1(15.775,27.325) 17.8,25.3 v1(18.45,25.3) ; 39.35,89.95 37.35,89.95 ; v1(46.675,87.9) 45.625,87.9 43.575,89.95 37.35,89.95
  Bottom Layer w0.3: R100.2@10.825,41.775 v1(10.825,42.35) ; Q2.3@13.2,42.475 v1(14.875,42.475) 15.445,41.905 15.445,41.88 15.55,41.775 C117.2@15.575,41.775
VDD_MCU: C29.1 C30.1 C31.1 C94.2 C97.1 C98.1 C99.1 C103.1 C106.1 C108.1 C111.1 C112.1 JP6.2 R20.1 R96.2 SB11.1 SB12.1 U28.D5 U28.D8 U28.D10 U28.E4 U28.E12 U28.H4 U28.J12 U28.L4 U28.M6 U28.M8 U28.M11 | length 30.9
  Top Layer w0.1: v2(52.425,52.225) 52.025,52.625 52.025,53.62 52.28,53.875 53.579,53.875 53.754,53.7 C31.1@56.7,53.7 ; v2(52.425,54.175) 53.6,54.175 54.05,54.625 C30.1@56.7,54.625 ; v2(52.425,56.125) 52.775,55.775 56.575,55.775 C29.1@56.7,55.65
  Top Layer w0.3: R20.1@60.3,50.5 60.46,50.5 60.63,50.33 JP6.2@60.63,47.95
  Bottom Layer w0.25: C108.1@40.5,50.7 v2(41.05,50.7) ; C106.1@40.5,52.55 v2(41.05,52.55) ; C103.1@40.5,57.125 v2(41.05,57.125) ; v2(45.9,44.25) R96.2@45.9,44.8 ; v2(46.575,53.525) U28.J12@46.9,53.85 ; v2(46.575,56.775) U28.E12@46.9,56.45 ; C99.1@47.2,62.225 47.275,62.15 v2(47.275,61.775) ; v2(47.225,51.575) U28.M11@47.55,51.9 ; v2(47.875,57.425) U28.D10@48.2,57.1 ; C98.1@48.1,62.225 48.175,62.15 v2(48.175,61.775) ; SB11.1@49.425,63.725 v2(49.425,64.825) ; U28.M8@49.5,51.9 v2(49.825,51.575) ; U28.D8@49.5,57.1 v2(49.825,57.425) ; C112.1@49.525,46.275 v2(49.525,46.825) ; U28.M6@50.8,51.9 v2(51.125,51.575) ; U28.D5@51.45,57.1 v2(51.775,57.425) ; C111.1@51.525,46.275 v2(51.525,46.825) ; U28.L4@52.1,52.55 v2(52.425,52.225) ; U28.H4@52.1,54.5 v2(52.425,54.175) ; U28.E4@52.1,56.45 v2(52.425,56.125)
  Bottom Layer w0.3: v2(51.625,61.7) C97.1@51.625,62.225 ; v2(52.65,61.7) C94.2@52.65,62.3 ; SB12.1@58.625,61.325 58.675,61.275 v2(59.85,61.275)
VDDA: C33.2 C55.2 R20.2 R21.1 U28.M1 | length 6.3
  Top Layer w0.3: v2(54.875,51.9) 56.75,51.9 57.625,51.9 R21.1@58.85,51.9 R20.2@60.3,51.9
  Bottom Layer w0.25: U28.M1@54.05,51.9 v2(54.875,51.9)
VIN: C32.2 CN14.1 JP3.1 U8.3 | length 5.6
  Bottom Layer w0.8: JP3.1@15.445,49.5 15.55,49.605 v1(15.55,52.225) ; v1(66.85,38.575) 67.742,37.683 69.19,37.683 CN14.1@69.298,37.575
  other v1: 66.85,39.475 66.85,40.375 15.125,53.725 15.925,54.375
VREFP: C35.2 C36.2 C110.1 R21.2 R95.2 U28.N1 | length 52.3
  Top Layer w0.3: v2(54.875,51.25) 56,51.25 C35.2@56.725,50.525 ; C35.2@56.75,50.525 58.825,50.525 R21.2@58.85,50.5 v1(58.85,49.75)
  Signal Layer 3 w0.5: v1(31.275,58.975) 30.675,58.375 30.675,52.113 32.888,49.9 36.4,49.9 38.85,49.9 41.066,47.684 41.066,46.784 44.625,43.225 48.85,43.225 51.5,45.875 54.275,45.875 55.35,46.95 55.35,50.775 v2@54.9,51.225
  Bottom Layer w0.25: U28.N1@54.05,51.25 v2(54.875,51.25)
  Bottom Layer w0.5: C110.1@28.1,59.45 R95.2@28.1,58.4 30.7,58.4 v1(31.275,58.975)
WAKEUP: B1.3 B1.4 C101.2 R36.2 U10.1 U28.E3 | length 42.2
  Top Layer w0.1: v2(56.35,59.425) 56.71,59.425 62.196,53.939 62.557,53.939 64.221,52.275 65.149,52.275 65.349,52.475 68.75,52.475 v1(69.425,51.8) ; v1(69.425,41.7) 68.675,41.7 R36.2@68.65,41.675 68.65,40.738 U10.1@68.637,40.725 69.15,40.725 69.525,41.1 70.05,41.1 B1.3@70.5,41.55 ; B1.4@70.5,36.837 B1.3@70.5,41.55 ; B1.3@70.5,42.437 B1.3@70.5,41.55
  Signal Layer 2 w0.1: v2(53.075,56.775) 54.95,56.775 56.35,58.175 v2(56.35,59.425) ; v1(69.425,41.7) v1(69.425,51.8)
  Bottom Layer w0.1: v2(56.35,59.425) 56.875,59.425 C101.2@56.925,59.475
  Bottom Layer w0.13: U28.E3@52.75,56.45 v2(53.075,56.775)
pads on no net: CN1.7 CN1.11 CN1.12 CN1.13 CN2.3 CN2.8 CN2.9 CN2.11 CN2.13 CN2.14 CN2.15 CN2.16 CN2.17 CN2.18 CN4.MT1 CN4.MT2 CN5.NPTH1 CN5.NPTH2 CN6.9 CN6.10 CN7.MT1 CN7.MT2 CN8.9 CN9.5 CN9.7 CN9.MT1 CN9.MT2 CN10.A2 CN10.A3 CN10.A8 CN10.A10 CN10.A11 CN10.B2 CN10.B3 CN10.B8 CN10.B10 CN10.B11 CN12.0 CN12.1 CN12.2 CN17.A2 CN17.A3 CN17.A8 CN17.A10 CN17.A11 CN17.B2 CN17.B3 CN17.B8 CN17.B10 CN17.B11 CN18.7 Designator90.1 Designator91.1 Designator92.1 Designator93.1 Designator94.1 Designator95.1 U1.4 U1.5 U4.4 U7.4 U7.5 U7.6 U7.7 U9.3 U11.4 U15.5 U19.4 U20.6 U22.A1 U22.A2 U22.A3 U22.A4 U22.A5 U22.A8 U22.A9 U22.A11 U22.A12 U22.A13 U22.B1 U22.B2 U22.B3 U22.B4 U22.B5 U22.B6 U22.B7 U22.B8 U22.B9 U22.B10 U22.B11 U22.B12 U22.B14 U22.B15 U22.C2 U22.C3 U22.C4 U22.C12 U22.C13 U22.C14 U22.C15 U22.D1 U22.D2 U22.D3 U22.D11 U22.D13 U22.D14 U22.E1 U22.E2 U22.E3 U22.E4 U22.E12 U22.E13 U22.E14 U22.E15 U22.F1 U22.F4 U22.F14 U22.G4 U22.G14 U22.G15 U22.H2 U22.H3 U22.H4 U22.H14 U22.J2 U22.J3 U22.J4 U22.K1 U22.K2 U22.K3 U22.K12 U22.K13 U22.K14 U22.K15 U22.L1 U22.L12 U22.L13 U22.L14 U22.L15 U22.M2 U22.M3 U22.M4 U22.M7 U22.M12 U22.M13 U22.M14 U22.M15 U22.N2 U22.N4 U22.N6 U22.N7 U22.N11 U22.N13 U22.N14 U22.N15 U22.P2 U22.P4 U22.P5 U22.P6 U22.P7 U22.P8 U22.P9 U22.P10 U22.P11 U22.P12 U22.P13 U22.P14 U22.P15 U22.R2 U22.R6 U22.R7 U22.R8 U22.R9 U22.R10 U22.R11 U22.R12 U22.R13 U23.7 U23.8 U23.9 U23.12 U23.13 U23.14 U23.17 U24.4 U25.19 U25.20 U25.23 U25.24 U27.3 U27.14 U28.A10 U28.C14 U28.G3 U28.H3 U28.J2 U28.K15 U28.N8 U29.A2 U29.A3 U29.B1 U29.B5 U31.5
copper on no net:
  other v1: 42.35,17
